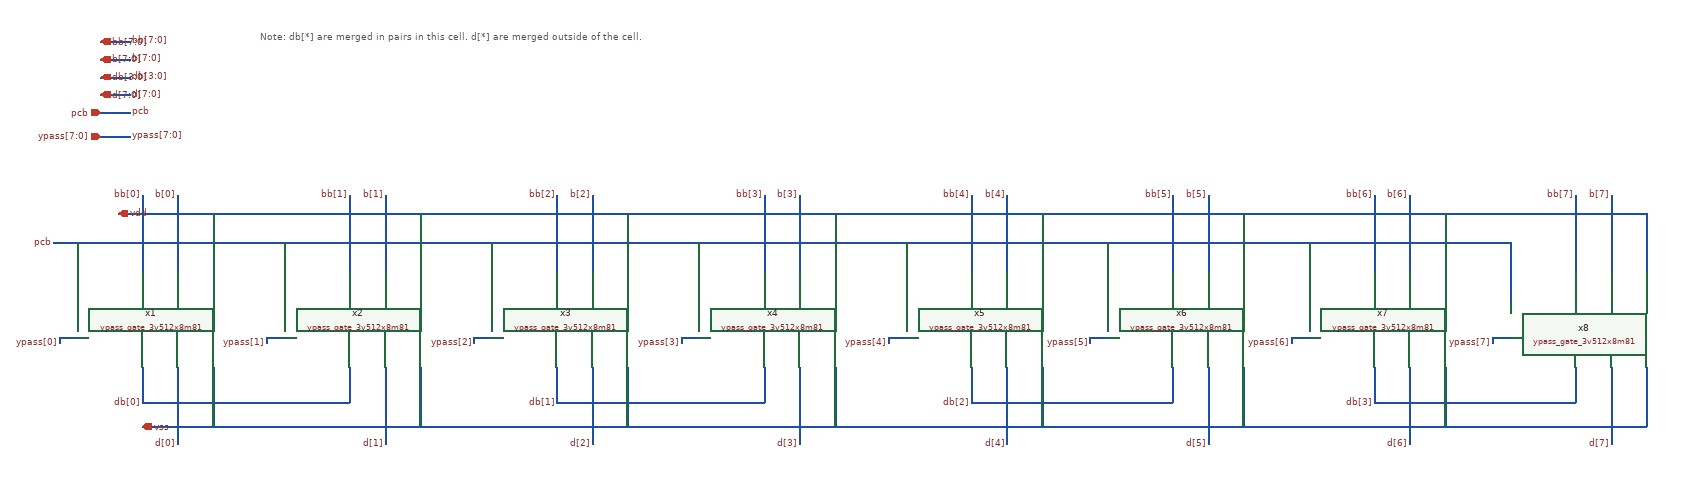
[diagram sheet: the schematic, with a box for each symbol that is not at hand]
v {xschem version=3.4.6 file_version=1.2}
G {}
K {}
V {}
S {}
E {}
T {Note:  db[*] are merged in pairs in this cell.  d[*] are merged outside of the cell.} 300 -440 0 0 0.4 0.4 {}
N 100 130 100 190 {lab=db[0]}
N 100 190 450 190 {lab=db[0]}
N 450 130 450 190 {lab=db[0]}
N 800 130 800 190 {lab=db[1]}
N 800 190 1150 190 {lab=db[1]}
N 1150 130 1150 190 {lab=db[1]}
N 1500 130 1500 190 {lab=db[2]}
N 1500 190 1840 190 {lab=db[2]}
N 1840 130 1840 190 {lab=db[2]}
N 2180 130 2180 190 {lab=db[3]}
N 2180 190 2520 190 {lab=db[3]}
N 2520 130 2520 190 {lab=db[3]}
N 2640 130 2640 230 {lab=vss}
N 100 230 2640 230 {lab=vss}
N 220 130 220 230 {lab=vss}
N 570 130 570 230 {lab=vss}
N 920 130 920 230 {lab=vss}
N 1270 130 1270 230 {lab=vss}
N 1620 130 1620 230 {lab=vss}
N 1960 130 1960 230 {lab=vss}
N 2300 130 2300 230 {lab=vss}
N 2640 -130 2640 -30 {lab=vdd}
N 60 -130 2640 -130 {lab=vdd}
N 220 -130 220 -30 {lab=vdd}
N -40 80 -10 80 {lab=ypass[0]}
N -50 -80 2410 -80 {lab=pcb}
N 2410 -80 2410 20 {lab=pcb}
N 2070 -80 2070 20 {lab=pcb}
N 1730 -80 1730 20 {lab=pcb}
N 1390 -80 1390 20 {lab=pcb}
N 1040 -80 1040 20 {lab=pcb}
N 690 -80 690 20 {lab=pcb}
N 340 -80 340 20 {lab=pcb}
N -10 -80 -10 20 {lab=pcb}
N 310 80 340 80 {lab=ypass[1]}
N 310 80 310 90 {lab=ypass[1]}
N -40 80 -40 90 {lab=ypass[0]}
N 660 80 690 80 {lab=ypass[2]}
N 660 80 660 90 {lab=ypass[2]}
N 100 -160 100 -30 {lab=bb[0]}
N 160 -160 160 -30 {lab=b[0]}
N 1010 80 1040 80 {lab=ypass[3]}
N 1010 80 1010 90 {lab=ypass[3]}
N 1360 80 1390 80 {lab=ypass[4]}
N 1360 80 1360 90 {lab=ypass[4]}
N 1700 80 1730 80 {lab=ypass[5]}
N 1700 80 1700 90 {lab=ypass[5]}
N 2040 80 2070 80 {lab=ypass[6]}
N 2040 80 2040 90 {lab=ypass[6]}
N 2380 80 2410 80 {lab=ypass[7]}
N 2380 80 2380 90 {lab=ypass[7]}
N 570 -130 570 -30 {lab=vdd}
N 450 -160 450 -30 {lab=bb[1]}
N 510 -160 510 -30 {lab=b[1]}
N 920 -130 920 -30 {lab=vdd}
N 800 -160 800 -30 {lab=bb[2]}
N 860 -160 860 -30 {lab=b[2]}
N 1270 -130 1270 -30 {lab=vdd}
N 1150 -160 1150 -30 {lab=bb[3]}
N 1210 -160 1210 -30 {lab=b[3]}
N 1620 -130 1620 -30 {lab=vdd}
N 1500 -160 1500 -30 {lab=bb[4]}
N 1560 -160 1560 -30 {lab=b[4]}
N 1960 -130 1960 -30 {lab=vdd}
N 1840 -160 1840 -30 {lab=bb[5]}
N 1900 -160 1900 -30 {lab=b[5]}
N 2300 -130 2300 -30 {lab=vdd}
N 2180 -160 2180 -30 {lab=bb[6]}
N 2240 -160 2240 -30 {lab=b[6]}
N 2520 -160 2520 -30 {lab=bb[7]}
N 2580 -160 2580 -30 {lab=b[7]}
N 30 -420 80 -420 {lab=bb[7:0]}
N 30 -390 80 -390 {lab=b[7:0]}
N 30 -360 80 -360 {lab=db[3:0]}
N 30 -300 80 -300 {lab=pcb}
N 30 -260 80 -260 {lab=ypass[7:0]}
N 160 130 160 260 {lab=d[0]}
N 510 130 510 260 {lab=d[1]}
N 860 130 860 260 {lab=d[2]}
N 1210 130 1210 260 {lab=d[3]}
N 1560 130 1560 260 {lab=d[4]}
N 1900 130 1900 260 {lab=d[5]}
N 2240 130 2240 260 {lab=d[6]}
N 2580 130 2580 260 {lab=d[7]}
N 30 -330 80 -330 {lab=d[7:0]}
C {ypass_gate_3v512x8m81.sym} 140 50 0 0 {name=x1}
C {ypass_gate_3v512x8m81.sym} 490 50 0 0 {name=x2}
C {ypass_gate_3v512x8m81.sym} 840 50 0 0 {name=x3}
C {ypass_gate_3v512x8m81.sym} 1190 50 0 0 {name=x4}
C {ypass_gate_3v512x8m81.sym} 1540 50 0 0 {name=x5}
C {ypass_gate_3v512x8m81.sym} 1880 50 0 0 {name=x6}
C {ypass_gate_3v512x8m81.sym} 2220 50 0 0 {name=x7}
C {lab_pin.sym} 100 190 0 0 {name=p1 sig_type=std_logic lab=db[0]}
C {lab_pin.sym} 800 190 0 0 {name=p2 sig_type=std_logic lab=db[1]}
C {lab_pin.sym} 1500 190 0 0 {name=p3 sig_type=std_logic lab=db[2]}
C {lab_pin.sym} 2180 190 0 0 {name=p4 sig_type=std_logic lab=db[3]}
C {iopin.sym} 60 -130 0 1 {name=p5 lab=vdd}
C {iopin.sym} 100 230 0 1 {name=p6 lab=vss}
C {lab_pin.sym} -40 90 3 0 {name=p7 sig_type=std_logic lab=ypass[0]}
C {lab_pin.sym} -50 -80 0 0 {name=p8 sig_type=std_logic lab=pcb}
C {lab_pin.sym} 310 90 3 0 {name=p9 sig_type=std_logic lab=ypass[1]}
C {lab_pin.sym} 660 90 3 0 {name=p10 sig_type=std_logic lab=ypass[2]}
C {lab_pin.sym} 100 -160 1 0 {name=p11 sig_type=std_logic lab=bb[0]}
C {lab_pin.sym} 160 -160 1 0 {name=p12 sig_type=std_logic lab=b[0]}
C {lab_pin.sym} 1010 90 3 0 {name=p13 sig_type=std_logic lab=ypass[3]}
C {lab_pin.sym} 1360 90 3 0 {name=p14 sig_type=std_logic lab=ypass[4]}
C {lab_pin.sym} 1700 90 3 0 {name=p15 sig_type=std_logic lab=ypass[5]}
C {lab_pin.sym} 2040 90 3 0 {name=p16 sig_type=std_logic lab=ypass[6]}
C {lab_pin.sym} 2380 90 3 0 {name=p17 sig_type=std_logic lab=ypass[7]}
C {lab_pin.sym} 450 -160 1 0 {name=p18 sig_type=std_logic lab=bb[1]}
C {lab_pin.sym} 510 -160 1 0 {name=p19 sig_type=std_logic lab=b[1]}
C {lab_pin.sym} 800 -160 1 0 {name=p20 sig_type=std_logic lab=bb[2]}
C {lab_pin.sym} 860 -160 1 0 {name=p21 sig_type=std_logic lab=b[2]}
C {lab_pin.sym} 1150 -160 1 0 {name=p22 sig_type=std_logic lab=bb[3]}
C {lab_pin.sym} 1210 -160 1 0 {name=p23 sig_type=std_logic lab=b[3]}
C {lab_pin.sym} 1500 -160 1 0 {name=p24 sig_type=std_logic lab=bb[4]}
C {lab_pin.sym} 1560 -160 1 0 {name=p25 sig_type=std_logic lab=b[4]}
C {lab_pin.sym} 1840 -160 1 0 {name=p26 sig_type=std_logic lab=bb[5]}
C {lab_pin.sym} 1900 -160 1 0 {name=p27 sig_type=std_logic lab=b[5]}
C {lab_pin.sym} 2180 -160 1 0 {name=p28 sig_type=std_logic lab=bb[6]}
C {lab_pin.sym} 2240 -160 1 0 {name=p29 sig_type=std_logic lab=b[6]}
C {lab_pin.sym} 2520 -160 1 0 {name=p30 sig_type=std_logic lab=bb[7]}
C {lab_pin.sym} 2580 -160 1 0 {name=p31 sig_type=std_logic lab=b[7]}
C {iopin.sym} 30 -420 0 1 {name=p32 lab=bb[7:0]}
C {iopin.sym} 30 -390 0 1 {name=p33 lab=b[7:0]}
C {iopin.sym} 30 -360 0 1 {name=p34 lab=db[3:0]}
C {ipin.sym} 30 -300 0 0 {name=p35 lab=pcb}
C {ipin.sym} 30 -260 0 0 {name=p36 lab=ypass[7:0]}
C {lab_pin.sym} 80 -420 0 1 {name=p37 sig_type=std_logic lab=bb[7:0]}
C {lab_pin.sym} 80 -390 0 1 {name=p38 sig_type=std_logic lab=b[7:0]}
C {lab_pin.sym} 80 -360 0 1 {name=p39 sig_type=std_logic lab=db[3:0]}
C {lab_pin.sym} 80 -300 0 1 {name=p40 sig_type=std_logic lab=pcb}
C {lab_pin.sym} 80 -260 0 1 {name=p41 sig_type=std_logic lab=ypass[7:0]}
C {lab_pin.sym} 160 260 3 0 {name=p42 sig_type=std_logic lab=d[0]}
C {lab_pin.sym} 510 260 3 0 {name=p43 sig_type=std_logic lab=d[1]}
C {lab_pin.sym} 860 260 3 0 {name=p44 sig_type=std_logic lab=d[2]}
C {lab_pin.sym} 1210 260 3 0 {name=p45 sig_type=std_logic lab=d[3]}
C {lab_pin.sym} 1560 260 3 0 {name=p46 sig_type=std_logic lab=d[4]}
C {lab_pin.sym} 1900 260 3 0 {name=p47 sig_type=std_logic lab=d[5]}
C {lab_pin.sym} 2240 260 3 0 {name=p48 sig_type=std_logic lab=d[6]}
C {lab_pin.sym} 2580 260 3 0 {name=p49 sig_type=std_logic lab=d[7]}
C {iopin.sym} 30 -330 0 1 {name=p50 lab=d[7:0]}
C {lab_pin.sym} 80 -330 0 1 {name=p51 sig_type=std_logic lab=d[7:0]}
C {ypass_gate_3v512x8m81.sym} 2560 50 0 0 {name=x8}
